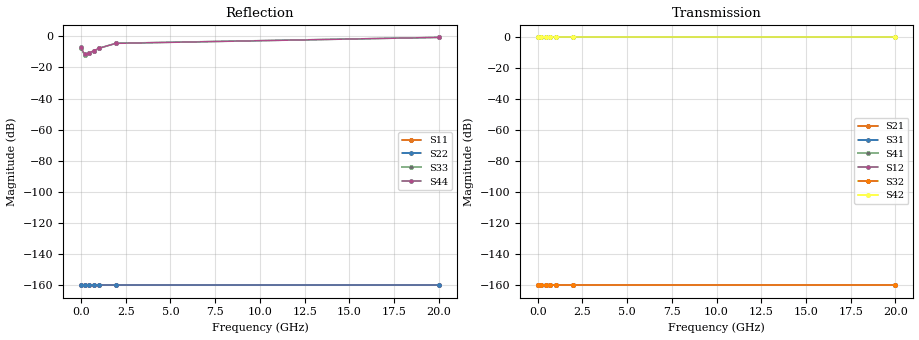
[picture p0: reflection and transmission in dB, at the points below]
! Generated on 07-29-2015 10:45:32
!  1 ----xxxxxxxxxxxxxxxxxx---- 3
!  xxxxxxxxxxxxxxxxxx
!  (Input) xxxxxxxxxxxxxxxxxx  (Output)
!  xxxxxxxxxxxxxxxxxx
!  2 ----xxxxxxxxxxxxxxxxxx---- 4
! FREQ  S11  S12  S13  S14
!  S21  S22  S23  S24
!  S31  S32  S33  S34
!  S41  S42  S43  S44
!  DB  ANG  DB  ANG  DB  ANG  DB  ANG
# HZ S DB R 50.00
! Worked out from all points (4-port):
!   861 points, 1 MHz to 20 GHz, reference 50 ohm
!   strongest paths, dB at 1 MHz, 11.89 MHz, 141.4 MHz, 1.682 GHz, 20 GHz:
!     S42: 0.0, 0.0, 0.0, 0.0, 0.0
!     S31: 0.0, 0.0, 0.0, 0.0, 0.0
!     S43: -17.5, -16.5, -18.8, -21.7, -23.0
!     S41: -, -, -, -, -
!     S32: -, -, -, -, -
!     S21: -, -, -, -, -
!   lowest |S11| = - dB at 1 MHz (marker M1), VSWR 1.00, Z = 50 + j5.27e-15 ohm
!   |S11| at or under -10 dB: start of sweep to end of sweep
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1000000  -300.00 177.0  -300.00 1.5  -300.00 2.3  -300.00 1.5
         -300.00 1.8  -300.00 177.2  -300.00 1.8  -300.00 2.3
         0.00 0.0  -300.00 1.5  -7.38 177.0  -17.91 1.5
         -300.00 1.8  0.00 0.0  -17.49 1.8  -7.02 177.2
1.9978e8  -300.00 -169.4  -300.00 -36.5  -300.00 -3.5  -300.00 -36.5
          -300.00 -28.7  -300.00 -169.9  -300.00 -28.7  -300.00 -3.5
          0.00 0.0  -300.00 -36.5  -12.10 -169.4  -20.74 -36.5
          -300.00 -28.7  0.00 0.0  -19.72 -28.7  -11.65 -169.9
4.7385e8  -300.00 -155.4  -300.00 -60.2  -300.00 -9.0  -300.00 -60.2
          -300.00 -38.5  -300.00 -157.2  -300.00 -38.5  -300.00 -9.0
          0.00 0.0  -300.00 -60.2  -10.94 -155.4  -28.37 -60.2
          -300.00 -38.5  0.00 0.0  -25.37 -38.5  -10.54 -157.2
7.17272e8  -300.00 -147.7  -300.00 6.4  -300.00 -14.1  -300.00 6.4
           -300.00 -12.5  -300.00 -150.0  -300.00 -12.5  -300.00 -13.9
           0.00 0.0  -300.00 6.4  -9.46 -147.7  -45.54 6.4
           -300.00 -12.5  0.00 0.0  -30.55 -12.5  -9.21 -150.0
1.02499e9  -300.00 -144.0  -300.00 69.9  -300.00 -20.1  -300.00 69.9
           -300.00 33.0  -300.00 -146.2  -300.00 33.0  -300.00 -19.6
           0.00 0.0  -300.00 69.9  -7.65 -144.0  -28.42 69.9
           -300.00 33.0  0.00 0.0  -27.97 33.0  -7.56 -146.2
1.95339e9  -300.00 -147.7  -300.00 40.5  -300.00 -33.1  -300.00 40.5
           -300.00 30.0  -300.00 -148.8  -300.00 30.0  -300.00 -32.1
           0.00 0.0  -300.00 40.5  -4.43 -147.7  -19.95 40.5
           -300.00 30.0  0.00 0.0  -20.57 30.0  -4.51 -148.8
2e10  -300.00 -171.6  -300.00 -41.3  -300.00 -58.6  -300.00 -41.3
      -300.00 -41.2  -300.00 -171.5  -300.00 -41.2  -300.00 -58.6
      0.00 0.0  -300.00 -41.3  -0.66 -171.6  -22.94 -41.3
      -300.00 -41.2  0.00 0.0  -22.97 -41.2  -0.66 -171.5
